VERSION 5.7 ;
BUSBITCHARS "[]" ;
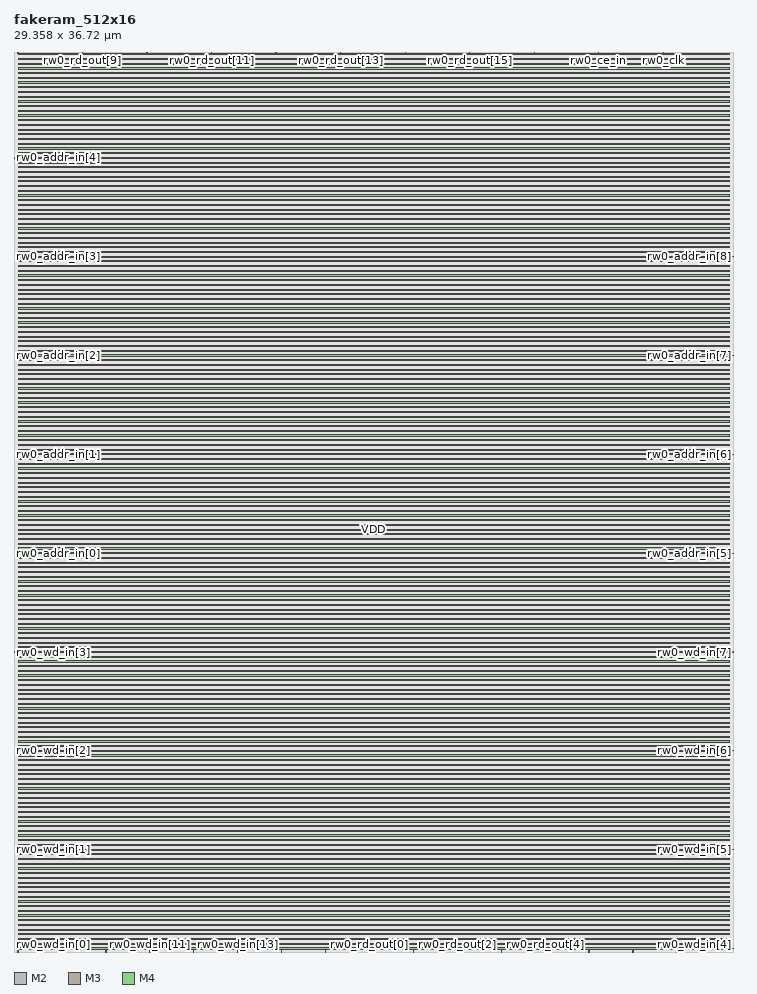
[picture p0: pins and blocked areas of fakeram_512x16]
MACRO fakeram_512x16
  FOREIGN fakeram_512x16 0 0 ;
  SYMMETRY X Y R90 ;
  SIZE 29.358 BY 36.720 ;
  CLASS BLOCK ;
  PIN rw0_wd_in[0]
    DIRECTION INPUT ;
    USE SIGNAL ;
    SHAPE ABUTMENT ;
    PORT
      LAYER M2 ;
      RECT 0.000 0.138 0.036 0.150 ;
    END
  END rw0_wd_in[0]
  PIN rw0_wd_in[1]
    DIRECTION INPUT ;
    USE SIGNAL ;
    SHAPE ABUTMENT ;
    PORT
      LAYER M2 ;
      RECT 0.000 4.170 0.036 4.182 ;
    END
  END rw0_wd_in[1]
  PIN rw0_wd_in[2]
    DIRECTION INPUT ;
    USE SIGNAL ;
    SHAPE ABUTMENT ;
    PORT
      LAYER M2 ;
      RECT 0.000 8.202 0.036 8.214 ;
    END
  END rw0_wd_in[2]
  PIN rw0_wd_in[3]
    DIRECTION INPUT ;
    USE SIGNAL ;
    SHAPE ABUTMENT ;
    PORT
      LAYER M2 ;
      RECT 0.000 12.234 0.036 12.246 ;
    END
  END rw0_wd_in[3]
  PIN rw0_wd_in[4]
    DIRECTION INPUT ;
    USE SIGNAL ;
    SHAPE ABUTMENT ;
    PORT
      LAYER M2 ;
      RECT 29.322 0.138 29.358 0.150 ;
    END
  END rw0_wd_in[4]
  PIN rw0_wd_in[5]
    DIRECTION INPUT ;
    USE SIGNAL ;
    SHAPE ABUTMENT ;
    PORT
      LAYER M2 ;
      RECT 29.322 4.170 29.358 4.182 ;
    END
  END rw0_wd_in[5]
  PIN rw0_wd_in[6]
    DIRECTION INPUT ;
    USE SIGNAL ;
    SHAPE ABUTMENT ;
    PORT
      LAYER M2 ;
      RECT 29.322 8.202 29.358 8.214 ;
    END
  END rw0_wd_in[6]
  PIN rw0_wd_in[7]
    DIRECTION INPUT ;
    USE SIGNAL ;
    SHAPE ABUTMENT ;
    PORT
      LAYER M2 ;
      RECT 29.322 12.234 29.358 12.246 ;
    END
  END rw0_wd_in[7]
  PIN rw0_wd_in[8]
    DIRECTION INPUT ;
    USE SIGNAL ;
    SHAPE ABUTMENT ;
    PORT
      LAYER M3 ;
      RECT 0.161 0.000 0.175 0.042 ;
    END
  END rw0_wd_in[8]
  PIN rw0_wd_in[9]
    DIRECTION INPUT ;
    USE SIGNAL ;
    SHAPE ABUTMENT ;
    PORT
      LAYER M3 ;
      RECT 1.953 0.000 1.967 0.042 ;
    END
  END rw0_wd_in[9]
  PIN rw0_wd_in[10]
    DIRECTION INPUT ;
    USE SIGNAL ;
    SHAPE ABUTMENT ;
    PORT
      LAYER M3 ;
      RECT 3.745 0.000 3.759 0.042 ;
    END
  END rw0_wd_in[10]
  PIN rw0_wd_in[11]
    DIRECTION INPUT ;
    USE SIGNAL ;
    SHAPE ABUTMENT ;
    PORT
      LAYER M3 ;
      RECT 5.537 0.000 5.551 0.042 ;
    END
  END rw0_wd_in[11]
  PIN rw0_wd_in[12]
    DIRECTION INPUT ;
    USE SIGNAL ;
    SHAPE ABUTMENT ;
    PORT
      LAYER M3 ;
      RECT 7.329 0.000 7.343 0.042 ;
    END
  END rw0_wd_in[12]
  PIN rw0_wd_in[13]
    DIRECTION INPUT ;
    USE SIGNAL ;
    SHAPE ABUTMENT ;
    PORT
      LAYER M3 ;
      RECT 9.121 0.000 9.135 0.042 ;
    END
  END rw0_wd_in[13]
  PIN rw0_wd_in[14]
    DIRECTION INPUT ;
    USE SIGNAL ;
    SHAPE ABUTMENT ;
    PORT
      LAYER M3 ;
      RECT 10.913 0.000 10.927 0.042 ;
    END
  END rw0_wd_in[14]
  PIN rw0_wd_in[15]
    DIRECTION INPUT ;
    USE SIGNAL ;
    SHAPE ABUTMENT ;
    PORT
      LAYER M3 ;
      RECT 12.705 0.000 12.719 0.042 ;
    END
  END rw0_wd_in[15]
  PIN rw0_rd_out[0]
    DIRECTION OUTPUT ;
    USE SIGNAL ;
    SHAPE ABUTMENT ;
    PORT
      LAYER M3 ;
      RECT 14.497 0.000 14.511 0.042 ;
    END
  END rw0_rd_out[0]
  PIN rw0_rd_out[1]
    DIRECTION OUTPUT ;
    USE SIGNAL ;
    SHAPE ABUTMENT ;
    PORT
      LAYER M3 ;
      RECT 16.289 0.000 16.303 0.042 ;
    END
  END rw0_rd_out[1]
  PIN rw0_rd_out[2]
    DIRECTION OUTPUT ;
    USE SIGNAL ;
    SHAPE ABUTMENT ;
    PORT
      LAYER M3 ;
      RECT 18.081 0.000 18.095 0.042 ;
    END
  END rw0_rd_out[2]
  PIN rw0_rd_out[3]
    DIRECTION OUTPUT ;
    USE SIGNAL ;
    SHAPE ABUTMENT ;
    PORT
      LAYER M3 ;
      RECT 19.873 0.000 19.887 0.042 ;
    END
  END rw0_rd_out[3]
  PIN rw0_rd_out[4]
    DIRECTION OUTPUT ;
    USE SIGNAL ;
    SHAPE ABUTMENT ;
    PORT
      LAYER M3 ;
      RECT 21.665 0.000 21.679 0.042 ;
    END
  END rw0_rd_out[4]
  PIN rw0_rd_out[5]
    DIRECTION OUTPUT ;
    USE SIGNAL ;
    SHAPE ABUTMENT ;
    PORT
      LAYER M3 ;
      RECT 23.457 0.000 23.471 0.042 ;
    END
  END rw0_rd_out[5]
  PIN rw0_rd_out[6]
    DIRECTION OUTPUT ;
    USE SIGNAL ;
    SHAPE ABUTMENT ;
    PORT
      LAYER M3 ;
      RECT 25.249 0.000 25.263 0.042 ;
    END
  END rw0_rd_out[6]
  PIN rw0_rd_out[7]
    DIRECTION OUTPUT ;
    USE SIGNAL ;
    SHAPE ABUTMENT ;
    PORT
      LAYER M3 ;
      RECT 27.041 0.000 27.055 0.042 ;
    END
  END rw0_rd_out[7]
  PIN rw0_rd_out[8]
    DIRECTION OUTPUT ;
    USE SIGNAL ;
    SHAPE ABUTMENT ;
    PORT
      LAYER M3 ;
      RECT 0.161 36.678 0.175 36.720 ;
    END
  END rw0_rd_out[8]
  PIN rw0_rd_out[9]
    DIRECTION OUTPUT ;
    USE SIGNAL ;
    SHAPE ABUTMENT ;
    PORT
      LAYER M3 ;
      RECT 2.793 36.678 2.807 36.720 ;
    END
  END rw0_rd_out[9]
  PIN rw0_rd_out[10]
    DIRECTION OUTPUT ;
    USE SIGNAL ;
    SHAPE ABUTMENT ;
    PORT
      LAYER M3 ;
      RECT 5.425 36.678 5.439 36.720 ;
    END
  END rw0_rd_out[10]
  PIN rw0_rd_out[11]
    DIRECTION OUTPUT ;
    USE SIGNAL ;
    SHAPE ABUTMENT ;
    PORT
      LAYER M3 ;
      RECT 8.057 36.678 8.071 36.720 ;
    END
  END rw0_rd_out[11]
  PIN rw0_rd_out[12]
    DIRECTION OUTPUT ;
    USE SIGNAL ;
    SHAPE ABUTMENT ;
    PORT
      LAYER M3 ;
      RECT 10.689 36.678 10.703 36.720 ;
    END
  END rw0_rd_out[12]
  PIN rw0_rd_out[13]
    DIRECTION OUTPUT ;
    USE SIGNAL ;
    SHAPE ABUTMENT ;
    PORT
      LAYER M3 ;
      RECT 13.321 36.678 13.335 36.720 ;
    END
  END rw0_rd_out[13]
  PIN rw0_rd_out[14]
    DIRECTION OUTPUT ;
    USE SIGNAL ;
    SHAPE ABUTMENT ;
    PORT
      LAYER M3 ;
      RECT 15.953 36.678 15.967 36.720 ;
    END
  END rw0_rd_out[14]
  PIN rw0_rd_out[15]
    DIRECTION OUTPUT ;
    USE SIGNAL ;
    SHAPE ABUTMENT ;
    PORT
      LAYER M3 ;
      RECT 18.585 36.678 18.599 36.720 ;
    END
  END rw0_rd_out[15]
  PIN rw0_addr_in[0]
    DIRECTION INPUT ;
    USE SIGNAL ;
    SHAPE ABUTMENT ;
    PORT
      LAYER M2 ;
      RECT 0.000 16.266 0.036 16.278 ;
    END
  END rw0_addr_in[0]
  PIN rw0_addr_in[1]
    DIRECTION INPUT ;
    USE SIGNAL ;
    SHAPE ABUTMENT ;
    PORT
      LAYER M2 ;
      RECT 0.000 20.298 0.036 20.310 ;
    END
  END rw0_addr_in[1]
  PIN rw0_addr_in[2]
    DIRECTION INPUT ;
    USE SIGNAL ;
    SHAPE ABUTMENT ;
    PORT
      LAYER M2 ;
      RECT 0.000 24.330 0.036 24.342 ;
    END
  END rw0_addr_in[2]
  PIN rw0_addr_in[3]
    DIRECTION INPUT ;
    USE SIGNAL ;
    SHAPE ABUTMENT ;
    PORT
      LAYER M2 ;
      RECT 0.000 28.362 0.036 28.374 ;
    END
  END rw0_addr_in[3]
  PIN rw0_addr_in[4]
    DIRECTION INPUT ;
    USE SIGNAL ;
    SHAPE ABUTMENT ;
    PORT
      LAYER M2 ;
      RECT 0.000 32.394 0.036 32.406 ;
    END
  END rw0_addr_in[4]
  PIN rw0_addr_in[5]
    DIRECTION INPUT ;
    USE SIGNAL ;
    SHAPE ABUTMENT ;
    PORT
      LAYER M2 ;
      RECT 29.322 16.266 29.358 16.278 ;
    END
  END rw0_addr_in[5]
  PIN rw0_addr_in[6]
    DIRECTION INPUT ;
    USE SIGNAL ;
    SHAPE ABUTMENT ;
    PORT
      LAYER M2 ;
      RECT 29.322 20.298 29.358 20.310 ;
    END
  END rw0_addr_in[6]
  PIN rw0_addr_in[7]
    DIRECTION INPUT ;
    USE SIGNAL ;
    SHAPE ABUTMENT ;
    PORT
      LAYER M2 ;
      RECT 29.322 24.330 29.358 24.342 ;
    END
  END rw0_addr_in[7]
  PIN rw0_addr_in[8]
    DIRECTION INPUT ;
    USE SIGNAL ;
    SHAPE ABUTMENT ;
    PORT
      LAYER M2 ;
      RECT 29.322 28.362 29.358 28.374 ;
    END
  END rw0_addr_in[8]
  PIN rw0_we_in
    DIRECTION INPUT ;
    USE SIGNAL ;
    SHAPE ABUTMENT ;
    PORT
      LAYER M3 ;
      RECT 21.217 36.678 21.231 36.720 ;
    END
  END rw0_we_in
  PIN rw0_ce_in
    DIRECTION INPUT ;
    USE SIGNAL ;
    SHAPE ABUTMENT ;
    PORT
      LAYER M3 ;
      RECT 23.849 36.678 23.863 36.720 ;
    END
  END rw0_ce_in
  PIN rw0_clk
    DIRECTION INPUT ;
    USE SIGNAL ;
    SHAPE ABUTMENT ;
    PORT
      LAYER M3 ;
      RECT 26.481 36.678 26.495 36.720 ;
    END
  END rw0_clk
  PIN VSS
    DIRECTION INOUT ;
    USE GROUND ;
    PORT
      LAYER M4 ;
      RECT 0.168 0.120 29.190 0.168 ;
      RECT 0.168 0.504 29.190 0.552 ;
      RECT 0.168 0.888 29.190 0.936 ;
      RECT 0.168 1.272 29.190 1.320 ;
      RECT 0.168 1.656 29.190 1.704 ;
      RECT 0.168 2.040 29.190 2.088 ;
      RECT 0.168 2.424 29.190 2.472 ;
      RECT 0.168 2.808 29.190 2.856 ;
      RECT 0.168 3.192 29.190 3.240 ;
      RECT 0.168 3.576 29.190 3.624 ;
      RECT 0.168 3.960 29.190 4.008 ;
      RECT 0.168 4.344 29.190 4.392 ;
      RECT 0.168 4.728 29.190 4.776 ;
      RECT 0.168 5.112 29.190 5.160 ;
      RECT 0.168 5.496 29.190 5.544 ;
      RECT 0.168 5.880 29.190 5.928 ;
      RECT 0.168 6.264 29.190 6.312 ;
      RECT 0.168 6.648 29.190 6.696 ;
      RECT 0.168 7.032 29.190 7.080 ;
      RECT 0.168 7.416 29.190 7.464 ;
      RECT 0.168 7.800 29.190 7.848 ;
      RECT 0.168 8.184 29.190 8.232 ;
      RECT 0.168 8.568 29.190 8.616 ;
      RECT 0.168 8.952 29.190 9.000 ;
      RECT 0.168 9.336 29.190 9.384 ;
      RECT 0.168 9.720 29.190 9.768 ;
      RECT 0.168 10.104 29.190 10.152 ;
      RECT 0.168 10.488 29.190 10.536 ;
      RECT 0.168 10.872 29.190 10.920 ;
      RECT 0.168 11.256 29.190 11.304 ;
      RECT 0.168 11.640 29.190 11.688 ;
      RECT 0.168 12.024 29.190 12.072 ;
      RECT 0.168 12.408 29.190 12.456 ;
      RECT 0.168 12.792 29.190 12.840 ;
      RECT 0.168 13.176 29.190 13.224 ;
      RECT 0.168 13.560 29.190 13.608 ;
      RECT 0.168 13.944 29.190 13.992 ;
      RECT 0.168 14.328 29.190 14.376 ;
      RECT 0.168 14.712 29.190 14.760 ;
      RECT 0.168 15.096 29.190 15.144 ;
      RECT 0.168 15.480 29.190 15.528 ;
      RECT 0.168 15.864 29.190 15.912 ;
      RECT 0.168 16.248 29.190 16.296 ;
      RECT 0.168 16.632 29.190 16.680 ;
      RECT 0.168 17.016 29.190 17.064 ;
      RECT 0.168 17.400 29.190 17.448 ;
      RECT 0.168 17.784 29.190 17.832 ;
      RECT 0.168 18.168 29.190 18.216 ;
      RECT 0.168 18.552 29.190 18.600 ;
      RECT 0.168 18.936 29.190 18.984 ;
      RECT 0.168 19.320 29.190 19.368 ;
      RECT 0.168 19.704 29.190 19.752 ;
      RECT 0.168 20.088 29.190 20.136 ;
      RECT 0.168 20.472 29.190 20.520 ;
      RECT 0.168 20.856 29.190 20.904 ;
      RECT 0.168 21.240 29.190 21.288 ;
      RECT 0.168 21.624 29.190 21.672 ;
      RECT 0.168 22.008 29.190 22.056 ;
      RECT 0.168 22.392 29.190 22.440 ;
      RECT 0.168 22.776 29.190 22.824 ;
      RECT 0.168 23.160 29.190 23.208 ;
      RECT 0.168 23.544 29.190 23.592 ;
      RECT 0.168 23.928 29.190 23.976 ;
      RECT 0.168 24.312 29.190 24.360 ;
      RECT 0.168 24.696 29.190 24.744 ;
      RECT 0.168 25.080 29.190 25.128 ;
      RECT 0.168 25.464 29.190 25.512 ;
      RECT 0.168 25.848 29.190 25.896 ;
      RECT 0.168 26.232 29.190 26.280 ;
      RECT 0.168 26.616 29.190 26.664 ;
      RECT 0.168 27.000 29.190 27.048 ;
      RECT 0.168 27.384 29.190 27.432 ;
      RECT 0.168 27.768 29.190 27.816 ;
      RECT 0.168 28.152 29.190 28.200 ;
      RECT 0.168 28.536 29.190 28.584 ;
      RECT 0.168 28.920 29.190 28.968 ;
      RECT 0.168 29.304 29.190 29.352 ;
      RECT 0.168 29.688 29.190 29.736 ;
      RECT 0.168 30.072 29.190 30.120 ;
      RECT 0.168 30.456 29.190 30.504 ;
      RECT 0.168 30.840 29.190 30.888 ;
      RECT 0.168 31.224 29.190 31.272 ;
      RECT 0.168 31.608 29.190 31.656 ;
      RECT 0.168 31.992 29.190 32.040 ;
      RECT 0.168 32.376 29.190 32.424 ;
      RECT 0.168 32.760 29.190 32.808 ;
      RECT 0.168 33.144 29.190 33.192 ;
      RECT 0.168 33.528 29.190 33.576 ;
      RECT 0.168 33.912 29.190 33.960 ;
      RECT 0.168 34.296 29.190 34.344 ;
      RECT 0.168 34.680 29.190 34.728 ;
      RECT 0.168 35.064 29.190 35.112 ;
      RECT 0.168 35.448 29.190 35.496 ;
      RECT 0.168 35.832 29.190 35.880 ;
      RECT 0.168 36.216 29.190 36.264 ;
      RECT 0.168 36.600 29.190 36.648 ;
    END
  END VSS
  PIN VDD
    DIRECTION INOUT ;
    USE POWER ;
    PORT
      LAYER M4 ;
      RECT 0.168 0.312 29.190 0.360 ;
      RECT 0.168 0.696 29.190 0.744 ;
      RECT 0.168 1.080 29.190 1.128 ;
      RECT 0.168 1.464 29.190 1.512 ;
      RECT 0.168 1.848 29.190 1.896 ;
      RECT 0.168 2.232 29.190 2.280 ;
      RECT 0.168 2.616 29.190 2.664 ;
      RECT 0.168 3.000 29.190 3.048 ;
      RECT 0.168 3.384 29.190 3.432 ;
      RECT 0.168 3.768 29.190 3.816 ;
      RECT 0.168 4.152 29.190 4.200 ;
      RECT 0.168 4.536 29.190 4.584 ;
      RECT 0.168 4.920 29.190 4.968 ;
      RECT 0.168 5.304 29.190 5.352 ;
      RECT 0.168 5.688 29.190 5.736 ;
      RECT 0.168 6.072 29.190 6.120 ;
      RECT 0.168 6.456 29.190 6.504 ;
      RECT 0.168 6.840 29.190 6.888 ;
      RECT 0.168 7.224 29.190 7.272 ;
      RECT 0.168 7.608 29.190 7.656 ;
      RECT 0.168 7.992 29.190 8.040 ;
      RECT 0.168 8.376 29.190 8.424 ;
      RECT 0.168 8.760 29.190 8.808 ;
      RECT 0.168 9.144 29.190 9.192 ;
      RECT 0.168 9.528 29.190 9.576 ;
      RECT 0.168 9.912 29.190 9.960 ;
      RECT 0.168 10.296 29.190 10.344 ;
      RECT 0.168 10.680 29.190 10.728 ;
      RECT 0.168 11.064 29.190 11.112 ;
      RECT 0.168 11.448 29.190 11.496 ;
      RECT 0.168 11.832 29.190 11.880 ;
      RECT 0.168 12.216 29.190 12.264 ;
      RECT 0.168 12.600 29.190 12.648 ;
      RECT 0.168 12.984 29.190 13.032 ;
      RECT 0.168 13.368 29.190 13.416 ;
      RECT 0.168 13.752 29.190 13.800 ;
      RECT 0.168 14.136 29.190 14.184 ;
      RECT 0.168 14.520 29.190 14.568 ;
      RECT 0.168 14.904 29.190 14.952 ;
      RECT 0.168 15.288 29.190 15.336 ;
      RECT 0.168 15.672 29.190 15.720 ;
      RECT 0.168 16.056 29.190 16.104 ;
      RECT 0.168 16.440 29.190 16.488 ;
      RECT 0.168 16.824 29.190 16.872 ;
      RECT 0.168 17.208 29.190 17.256 ;
      RECT 0.168 17.592 29.190 17.640 ;
      RECT 0.168 17.976 29.190 18.024 ;
      RECT 0.168 18.360 29.190 18.408 ;
      RECT 0.168 18.744 29.190 18.792 ;
      RECT 0.168 19.128 29.190 19.176 ;
      RECT 0.168 19.512 29.190 19.560 ;
      RECT 0.168 19.896 29.190 19.944 ;
      RECT 0.168 20.280 29.190 20.328 ;
      RECT 0.168 20.664 29.190 20.712 ;
      RECT 0.168 21.048 29.190 21.096 ;
      RECT 0.168 21.432 29.190 21.480 ;
      RECT 0.168 21.816 29.190 21.864 ;
      RECT 0.168 22.200 29.190 22.248 ;
      RECT 0.168 22.584 29.190 22.632 ;
      RECT 0.168 22.968 29.190 23.016 ;
      RECT 0.168 23.352 29.190 23.400 ;
      RECT 0.168 23.736 29.190 23.784 ;
      RECT 0.168 24.120 29.190 24.168 ;
      RECT 0.168 24.504 29.190 24.552 ;
      RECT 0.168 24.888 29.190 24.936 ;
      RECT 0.168 25.272 29.190 25.320 ;
      RECT 0.168 25.656 29.190 25.704 ;
      RECT 0.168 26.040 29.190 26.088 ;
      RECT 0.168 26.424 29.190 26.472 ;
      RECT 0.168 26.808 29.190 26.856 ;
      RECT 0.168 27.192 29.190 27.240 ;
      RECT 0.168 27.576 29.190 27.624 ;
      RECT 0.168 27.960 29.190 28.008 ;
      RECT 0.168 28.344 29.190 28.392 ;
      RECT 0.168 28.728 29.190 28.776 ;
      RECT 0.168 29.112 29.190 29.160 ;
      RECT 0.168 29.496 29.190 29.544 ;
      RECT 0.168 29.880 29.190 29.928 ;
      RECT 0.168 30.264 29.190 30.312 ;
      RECT 0.168 30.648 29.190 30.696 ;
      RECT 0.168 31.032 29.190 31.080 ;
      RECT 0.168 31.416 29.190 31.464 ;
      RECT 0.168 31.800 29.190 31.848 ;
      RECT 0.168 32.184 29.190 32.232 ;
      RECT 0.168 32.568 29.190 32.616 ;
      RECT 0.168 32.952 29.190 33.000 ;
      RECT 0.168 33.336 29.190 33.384 ;
      RECT 0.168 33.720 29.190 33.768 ;
      RECT 0.168 34.104 29.190 34.152 ;
      RECT 0.168 34.488 29.190 34.536 ;
      RECT 0.168 34.872 29.190 34.920 ;
      RECT 0.168 35.256 29.190 35.304 ;
      RECT 0.168 35.640 29.190 35.688 ;
      RECT 0.168 36.024 29.190 36.072 ;
      RECT 0.168 36.408 29.190 36.456 ;
    END
  END VDD
  OBS
    LAYER M1 ;
    RECT 0 0 29.358 36.720 ;
    LAYER M2 ;
    RECT 0 0 29.358 36.720 ;
    LAYER M3 ;
    RECT 0 0 29.358 36.720 ;
    LAYER M4 ;
    RECT 0 0 29.358 36.720 ;
  END
END fakeram_512x16

END LIBRARY
